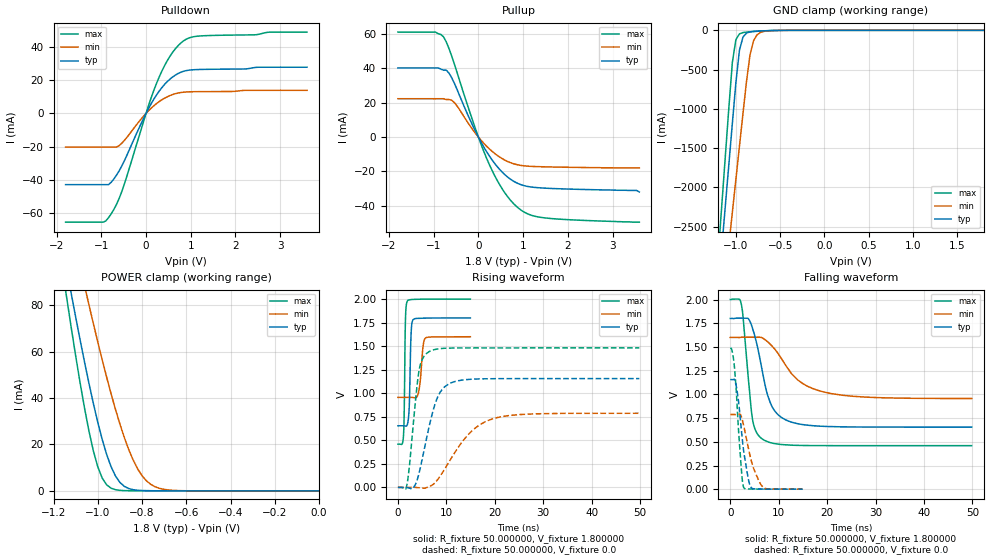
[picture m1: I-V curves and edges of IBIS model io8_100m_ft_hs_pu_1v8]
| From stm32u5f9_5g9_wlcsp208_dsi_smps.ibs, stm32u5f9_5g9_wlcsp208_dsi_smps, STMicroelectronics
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|   Model io8_100m_ft_hs_pu_1v8
[Model]  io8_100m_ft_hs_pu_1v8
Model_type I/O
Polarity   Non-Inverting
Enable   Active-Low
Vinl =   0.540000V
Vinh =   1.260000V
Vmeas =  0.900000V
Cref =   50.000000pF
Rref =   100.000000M
Vref =   0.0V
C_comp   3.148300pF   3.147400pF   3.196500pF
[Temperature Range]   25.000000   0.140000k   -40.000000
[Pullup Reference]   1.800000V   1.600000V   2.000000V
[Pulldown Reference]   0.0V   0.0V   0.0V
[POWER Clamp Reference]   1.800000V   1.600000V   2.000000V
[GND Clamp Reference]   0.0V   0.0V   0.0V
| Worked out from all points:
|   slope of the pulldown table from 0 to 0.27 V, typ, clamps not added: 21.7 ohm
|   slope of the pullup table from 0 to 0.27 V, typ, clamps not added: 22.6 ohm
|   GND clamp passes 1 mA (typ) near -0.51 V on its own axis
|   POWER clamp passes 1 mA (typ) near -0.86 V on its own axis
|   rising waveform, R_fixture 50.000000, V_fixture 1.800000: 20-80 % time 320ps typ, 625ps min, 232ps max; typ from 0.655 V to 1.8 V
|   rising waveform, R_fixture 50.000000, V_fixture 0.0: 20-80 % time 3.21ns typ, 6.76ns min, 1.69ns max; typ from 0.001 V to 1.16 V
|   falling waveform, R_fixture 50.000000, V_fixture 1.800000: 20-80 % time 3.22ns typ, 6.73ns min, 1.65ns max; typ from 1.8 V to 0.655 V
|   falling waveform, R_fixture 50.000000, V_fixture 0.0: 20-80 % time 1.6ns typ, 2.38ns min, 1.14ns max; typ from 1.16 V to 0.001 V
[Pulldown]
|Voltage   I(typ)   I(min)   I(max)
-1.8V     -42.74mA   -20.21mA   -65.25mA
-960mV    -42.74mA   -20.21mA   -65.25mA
-780mV    -41.3mA    -20.21mA   -60.25mA
-660mV    -37mA      -20.2mA    -54.5mA
-540mV    -31.39mA   -17.82mA   -46.65mA
0V        0A         0A         0A
240mV     11.28mA    6.002mA    18.38mA
480mV     19.17mA    10.02mA    31.83mA
780mV     24.67mA    12.5mA     42.21mA
960mV     25.9mA     12.9mA     45.21mA
1.2V      26.29mA    13.01mA    46.37mA
3.6V      27.65mA    13.81mA    48.71mA
[Pullup]
|Voltage   I(typ)   I(min)   I(max)
-1.8V     40.31mA    22.36mA    61.21mA
-960mV    40.31mA    22.36mA    61.21mA
-780mV    39.02mA    22.36mA    58.45mA
-660mV    37.4mA     21.91mA    51.75mA
-540mV    31.51mA    20.18mA    42.77mA
-120mV    6.338mA    4.065mA    8.965mA
240mV     -10.82mA   -6.752mA   -15.73mA
540mV     -20.62mA   -12.68mA   -30.5mA
900mV     -27.22mA   -16.28mA   -41.49mA
1.14V     -28.94mA   -17mA      -45.14mA
1.5V      -29.77mA   -17.34mA   -47.14mA
3.6V      -32mA      -18mA      -49.6mA
[GND_clamp]
|Voltage   I(typ)   I(min)   I(max)
-1.8V     -9.707A    -9.942A    -9.774A
-1.2V     -3.309A    -4.006A    -2.864A
-1.16V    -2.777A    -3.584A    -2.239A
-1.12V    -2.246A    -3.162A    -1.614A
-1.04V    -1.186A    -2.319A    -408.6mA
-1V       -663.9mA   -1.898A    -117.8mA
-960mV    -254mA     -1.478A    -45.14mA
-920mV    -86.03mA   -1.06A     -28.58mA
-840mV    -19.12mA   -308.9mA   -18.74mA
-800mV    -13.39mA   -130.8mA   -15.31mA
-720mV    -7.948mA   -25.37mA   -9.381mA
1.8V      0A         14.97nA    0A
[POWER_clamp]
|Voltage   I(typ)   I(min)   I(max)
-1.8V     470.9mA    433.7mA    554.6mA
-1.14V    95.28mA    122.7mA    82.88mA
-1.12V    85mA       114mA      70.34mA
-1.06V    55.55mA    88.43mA    35.73mA
-1.04V    46.38mA    80.17mA    25.83mA
-1V       29.54mA    64.14mA    10.37mA
-940mV    10.43mA    41.88mA    1.177mA
-900mV    3.66mA     28.79mA    250.5uA
-840mV    527.2uA    13.26mA    95.74uA
-800mV    153.8uA    6.55mA     88.56uA
-740mV    60.02uA    1.742mA    70.74uA
0V        0A         18.15nA    0A
[Ramp]
| variable   typ   min   max
dV/dt_r  0.69287/3.20241n   0.47199/6.75267n   0.88855/1.68963n
dV/dt_f  0.68715/3.21683n   0.38620/6.71772n   0.92440/1.65102n
R_load = 50.000000
[Rising Waveform]
R_fixture= 50.000000
V_fixture= 1.800000
V_fixture_min= 1.600000
V_fixture_max= 2.000000
|time   V(typ)   V(min)   V(max)
0s        654.8mV    956mV      459.4mV
1.141ns   654.6mV    956mV      544.2mV
1.562ns   651.7mV    956mV      1.793V
1.922ns   664.5mV    956.1mV    1.977V
2.312ns   832.9mV    956.1mV    1.991V
2.733ns   1.647V     955.9mV    1.995V
3.123ns   1.78V      954.9mV    1.996V
4.324ns   1.795V     1.027V     1.998V
5.676ns   1.798V     1.586V     1.999V
14.95ns   1.8V       1.6V       2V
[Rising Waveform]
R_fixture= 50.000000
V_fixture= 0.0
V_fixture_min= 0.0
V_fixture_max= 0.0
|time   V(typ)   V(min)   V(max)
0s        614.4uV    691.1uV    579uV
1.802ns   -969.1uV   688.6uV    15.4mV
3.003ns   -12.87mV   799.3uV    577.5mV
4.304ns   139.8mV    -3.18mV    1.223V
6.406ns   638mV      8.75mV     1.441V
8.008ns   935.3mV    71.01mV    1.469V
9.61ns    1.066V     191.7mV    1.478V
14.41ns   1.146V     554.9mV    1.481V
18.92ns   1.154V     716.9mV    1.481V
49.85ns   1.155V     787.4mV    1.481V
[Falling Waveform]
R_fixture= 50.000000
V_fixture= 1.800000
V_fixture_min= 1.600000
V_fixture_max= 2.000000
|time   V(typ)   V(min)   V(max)
0s        1.8V       1.6V       2V
2.302ns   1.804V     1.602V     1.946V
4.605ns   1.695V     1.603V     734mV
5.506ns   1.526V     1.602V     591.6mV
7.007ns   1.143V     1.582V     516.6mV
8.408ns   894.7mV    1.521V     489.5mV
10.11ns   774.9mV    1.412V     474mV
13.91ns   690.8mV    1.153V     462.5mV
18.42ns   665mV      1.037V     459.8mV
49.85ns   654.8mV    956mV      459.4mV
[Falling Waveform]
R_fixture= 50.000000
V_fixture= 0.0
V_fixture_min= 0.0
V_fixture_max= 0.0
|time   V(typ)   V(min)   V(max)
0s        1.155V     787.4mV    1.481V
270.3ps   1.155V     787.4mV    1.479V
660.7ps   1.156V     787.4mV    1.377V
1.231ns   1.091V     787.4mV    1.044V
1.682ns   935.7mV    788.4mV    643.8mV
2.252ns   646.4mV    770.7mV    236.8mV
2.763ns   406.1mV    672.2mV    19.93mV
4.144ns   31.46mV    340.5mV    2.096mV
6.787ns   1.826mV    20.06mV    1.003mV
14.95ns   614.4uV    691.1uV    579uV
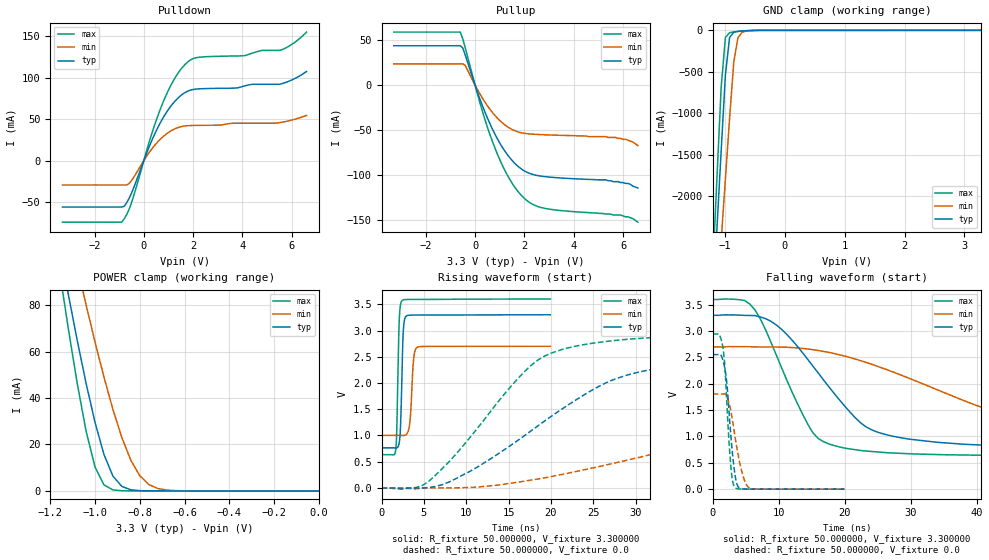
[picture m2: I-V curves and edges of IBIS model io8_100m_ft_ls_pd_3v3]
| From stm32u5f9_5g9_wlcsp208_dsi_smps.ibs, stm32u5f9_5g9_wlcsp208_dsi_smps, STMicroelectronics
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|   Model io8_100m_ft_ls_pd_3v3
[Model]  io8_100m_ft_ls_pd_3v3
Model_type I/O
Polarity   Non-Inverting
Enable   Active-Low
Vinl =   0.990000V
Vinh =   2.310000V
Vmeas =  1.650000V
Cref =   50.000000pF
Rref =   100.000000M
Vref =   0.0V
C_comp   3.313100pF   3.281800pF   3.354500pF
[Temperature Range]   25.000000   0.140000k   -40.000000
[Pullup Reference]   3.300000V   2.700000V   3.600000V
[Pulldown Reference]   0.0V   0.0V   0.0V
[POWER Clamp Reference]   3.300000V   2.700000V   3.600000V
[GND Clamp Reference]   0.0V   0.0V   0.0V
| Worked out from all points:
|   slope of the pulldown table from 0 to 0.495 V, typ, clamps not added: 14 ohm
|   slope of the pullup table from 0 to 0.495 V, typ, clamps not added: 13.7 ohm
|   GND clamp passes 1 mA (typ) near -0.50 V on its own axis
|   POWER clamp passes 1 mA (typ) near -0.85 V on its own axis
|   rising waveform, R_fixture 50.000000, V_fixture 3.300000: 20-80 % time 251ps typ, 341ps min, 235ps max; typ from 0.764 V to 3.3 V
|   rising waveform, R_fixture 50.000000, V_fixture 0.0: 20-80 % time 14.6ns typ, 31.2ns min, 9.33ns max; typ from 0 V to 2.55 V
|   falling waveform, R_fixture 50.000000, V_fixture 3.300000: 20-80 % time 10ns typ, 23.1ns min, 6.36ns max; typ from 3.3 V to 0.764 V
|   falling waveform, R_fixture 50.000000, V_fixture 0.0: 20-80 % time 1.02ns typ, 1.54ns min, 817ps max; typ from 2.55 V to 0 V
[Pulldown]
|Voltage   I(typ)   I(min)   I(max)
-3.3V     -56.06mA   -29.42mA   -74.35mA
-900mV    -56.06mA   -29.42mA   -74.35mA
-700mV    -51.09mA   -29.42mA   -65.48mA
-500mV    -39.32mA   -24.2mA    -50.88mA
300mV     22.62mA    13.13mA    30.42mA
800mV     52.54mA    29.36mA    71.75mA
1.3V      72.91mA    38.82mA    101.4mA
1.8V      84.02mA    42.13mA    119.4mA
2.2V      86.43mA    42.46mA    124.5mA
5.5V      91.98mA    45.75mA    132.9mA
6.1V      98.6mA     49.6mA     142.1mA
6.6V      107.5mA    54.5mA     155mA
[Pullup]
|Voltage   I(typ)   I(min)   I(max)
-3.3V     43.8mA     23.72mA    58.97mA
-600mV    43.8mA     23.72mA    58.97mA
-500mV    41.28mA    23.72mA    51.53mA
-400mV    33.57mA    21.9mA     41.51mA
300mV     -22.93mA   -14.5mA    -29.27mA
800mV     -54.04mA   -33.36mA   -69.41mA
1.4V      -80.24mA   -47.59mA   -104.2mA
2.1V      -96.56mA   -53.73mA   -127.9mA
3V        -101.9mA   -55.18mA   -137.5mA
5.7V      -107mA     -58mA      -144mA
6.2V      -109mA     -61mA      -146mA
6.6V      -114mA     -67mA      -152mA
[GND_clamp]
|Voltage   I(typ)   I(min)   I(max)
-3.3V     -9.848A    -9.957A    -9.458A
-1.2V     -3.312A    -4.013A    -2.863A
-1.13V    -2.381A    -3.274A    -1.769A
-1.06V    -1.452A    -2.535A    -684.8mA
-990mV    -542.9mA   -1.798A    -88.04mA
-920mV    -87.13mA   -1.064A    -28.45mA
-850mV    -22.11mA   -382.4mA   -19.62mA
-780mV    -11.98mA   -86.98mA   -13.73mA
-710mV    -7.63mA    -22.27mA   -8.759mA
-640mV    -4.504mA   -7.781mA   -4.831mA
-360mV    -39.8uA    -178.9uA   -19.56uA
3.28V     83.52uA    56.87uA    102.4uA
[POWER_clamp]
|Voltage   I(typ)   I(min)   I(max)
-3.28V    1.355A     1.167A     1.664A
-1.16V    105.7mA    131.6mA    95.69mA
-1.12V    84.97mA    114mA      70.27mA
-1.08V    65.05mA    96.83mA    46.54mA
-1.04V    46.34mA    80.15mA    25.76mA
-1V       29.51mA    64.13mA    10.3mA
-960mV    15.69mA    48.99mA    2.571mA
-920mV    6.373mA    35.1mA     455.6uA
-840mV    490.7uA    13.24mA    11.36uA
-760mV    27.33uA    2.767mA    276.6nA
-640mV    346.6nA    134.1uA    15.62nA
0V        0A         19.91nA    0A
[Ramp]
| variable   typ   min   max
dV/dt_r  1.53198/14.61283n   1.08390/31.21037n   1.76610/9.31984n
dV/dt_f  1.52119/10.01542n   1.01874/23.04554n   1.77923/6.35235n
R_load = 50.000000
[Rising Waveform]
R_fixture= 50.000000
V_fixture= 3.300000
V_fixture_min= 2.700000
V_fixture_max= 3.600000
|time   V(typ)   V(min)   V(max)
0s        763.9mV    1.001V     633.7mV
1.682ns   762.1mV    1.001V     731.3mV
2.082ns   852.8mV    1.001V     3.161V
2.242ns   1.169V     1.001V     3.494V
2.442ns   2.343V     1V         3.573V
2.763ns   3.233V     1.002V     3.589V
3.323ns   3.292V     1.217V     3.592V
3.804ns   3.294V     2.474V     3.592V
4.204ns   3.295V     2.678V     3.592V
19.94ns   3.299V     2.699V     3.599V
[Rising Waveform]
R_fixture= 50.000000
V_fixture= 0.0
V_fixture_min= 0.0
V_fixture_max= 0.0
|time   V(typ)   V(min)   V(max)
0s        16.97nV    116.6nV    53.79nV
5.606ns   7.053mV    -445.1uV   129.4mV
11.21ns   387mV      14.86mV    1.114V
16.02ns   896.6mV    107.2mV    2.068V
19.22ns   1.27V      190.8mV    2.509V
27.23ns   2.053V     462.6mV    2.804V
35.24ns   2.34V      768.8mV    2.889V
59.26ns   2.52V      1.515V     2.939V
95.3ns    2.551V     1.753V     2.943V
398.8ns   2.553V     1.806V     2.943V
[Falling Waveform]
R_fixture= 50.000000
V_fixture= 3.300000
V_fixture_min= 2.700000
V_fixture_max= 3.600000
|time   V(typ)   V(min)   V(max)
0s        3.299V     2.699V     3.599V
4.805ns   3.297V     2.704V     3.582V
6.406ns   3.293V     2.7V       3.4V
10.41ns   3.034V     2.697V     2.308V
16.02ns   2.199V     2.631V     958.7mV
22.42ns   1.256V     2.437V     733.4mV
26.43ns   1.029V     2.265V     691.3mV
47.25ns   808mV      1.344V     639.5mV
76.88ns   770.4mV    1.085V     634.1mV
398.8ns   763.9mV    1.001V     633.7mV
[Falling Waveform]
R_fixture= 50.000000
V_fixture= 0.0
V_fixture_min= 0.0
V_fixture_max= 0.0
|time   V(typ)   V(min)   V(max)
0s        2.553V     1.806V     2.943V
920.9ps   2.553V     1.806V     2.943V
1.562ns   2.437V     1.807V     2.658V
1.842ns   2.277V     1.81V      2.312V
2.082ns   2.07V      1.762V     1.751V
2.683ns   1.099V     1.52V      509.2mV
3.323ns   308.5mV    1.031V     36.82mV
4.484ns   4.69mV     293mV      1.824mV
5.606ns   952.3uV    16.21mV    1.484mV
19.94ns   16.97nV    116.6nV    53.79nV
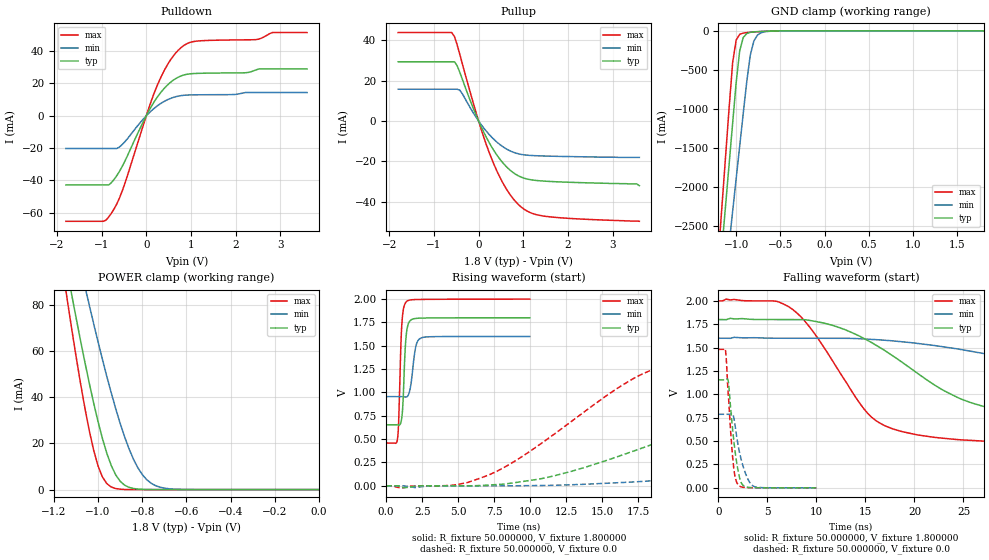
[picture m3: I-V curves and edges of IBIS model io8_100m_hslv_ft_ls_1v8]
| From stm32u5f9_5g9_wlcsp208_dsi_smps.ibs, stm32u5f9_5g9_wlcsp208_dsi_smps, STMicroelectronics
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|   Model io8_100m_hslv_ft_ls_1v8
[Model]  io8_100m_hslv_ft_ls_1v8
Model_type I/O
Polarity   Non-Inverting
Enable   Active-Low
Vinl =   0.540000V
Vinh =   1.260000V
Vmeas =  0.900000V
Cref =   50.000000pF
Rref =   100.000000M
Vref =   0.0V
C_comp   3.235100pF   3.233100pF   3.282800pF
[Temperature Range]   25.000000   0.140000k   -40.000000
[Pullup Reference]   1.800000V   1.600000V   2.000000V
[Pulldown Reference]   0.0V   0.0V   0.0V
[POWER Clamp Reference]   1.800000V   1.600000V   2.000000V
[GND Clamp Reference]   0.0V   0.0V   0.0V
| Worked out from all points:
|   slope of the pulldown table from 0 to 0.27 V, typ, clamps not added: 21.7 ohm
|   slope of the pullup table from 0 to 0.27 V, typ, clamps not added: 22.6 ohm
|   GND clamp passes 1 mA (typ) near -0.51 V on its own axis
|   POWER clamp passes 1 mA (typ) near -0.86 V on its own axis
|   rising waveform, R_fixture 50.000000, V_fixture 1.800000: 20-80 % time 203ps typ, 315ps min, 190ps max; typ from 0.654 V to 1.8 V
|   rising waveform, R_fixture 50.000000, V_fixture 0.0: 20-80 % time 14.5ns typ, 29.3ns min, 8.35ns max; typ from 0 V to 1.16 V
|   falling waveform, R_fixture 50.000000, V_fixture 1.800000: 20-80 % time 11.3ns typ, 24.9ns min, 6.01ns max; typ from 1.8 V to 0.654 V
|   falling waveform, R_fixture 50.000000, V_fixture 0.0: 20-80 % time 734ps typ, 1ns min, 580ps max; typ from 1.16 V to 0 V
[Pulldown]
|Voltage   I(typ)   I(min)   I(max)
-1.8V     -42.74mA   -20.21mA   -65.25mA
-960mV    -42.74mA   -20.21mA   -65.25mA
-780mV    -41.3mA    -20.21mA   -60.25mA
-540mV    -31.39mA   -17.82mA   -46.65mA
0V        -10fA      -1pA       10fA
240mV     11.28mA    6.001mA    18.38mA
480mV     19.18mA    10.01mA    31.83mA
780mV     24.67mA    12.49mA    42.21mA
1.14V     26.24mA    12.99mA    46.23mA
2.46V     28.42mA    14.38mA    47.14mA
2.82V     29mA       14.38mA    51.49mA
3.6V      29mA       14.38mA    51.49mA
[Pullup]
|Voltage   I(typ)   I(min)   I(max)
-1.8V     29.28mA    15.71mA    43.71mA
-600mV    29.28mA    15.71mA    43.71mA
-540mV    29.28mA    15.71mA    41.72mA
-420mV    24.04mA    15.23mA    32.87mA
0V        630fA      250pA      0A
300mV     -13.1mA    -8.157mA   -19.11mA
600mV     -22.1mA    -13.53mA   -32.82mA
780mV     -25.61mA   -15.48mA   -38.6mA
960mV     -27.82mA   -16.55mA   -42.66mA
1.2V      -29.16mA   -17.08mA   -45.68mA
1.56V     -29.85mA   -17.37mA   -47.3mA
3.6V      -32mA      -18mA      -49.6mA
[GND_clamp]
|Voltage   I(typ)   I(min)   I(max)
-1.8V     -9.707A    -9.942A    -9.774A
-1.2V     -3.309A    -4.006A    -2.864A
-1.16V    -2.777A    -3.584A    -2.239A
-1.12V    -2.246A    -3.162A    -1.614A
-1.04V    -1.186A    -2.319A    -408.6mA
-1V       -663.9mA   -1.898A    -117.8mA
-960mV    -254mA     -1.478A    -45.14mA
-920mV    -86.03mA   -1.06A     -28.58mA
-840mV    -19.12mA   -308.9mA   -18.74mA
-800mV    -13.39mA   -130.8mA   -15.31mA
-720mV    -7.948mA   -25.37mA   -9.381mA
1.8V      0A         14.95nA    0A
[POWER_clamp]
|Voltage   I(typ)   I(min)   I(max)
-1.8V     470.8mA    433.7mA    554.6mA
-1.14V    95.25mA    122.7mA    82.82mA
-1.12V    84.97mA    114mA      70.27mA
-1.06V    55.51mA    88.42mA    35.67mA
-1.04V    46.34mA    80.15mA    25.76mA
-1V       29.51mA    64.13mA    10.3mA
-940mV    10.39mA    41.86mA    1.109mA
-900mV    3.624mA    28.77mA    182.8uA
-840mV    490.7uA    13.24mA    11.35uA
-800mV    116.8uA    6.532mA    1.77uA
-740mV    13.2uA     1.723mA    109.2nA
0V        0A         18.72nA    0A
[Ramp]
| variable   typ   min   max
dV/dt_r  0.69300/14.45421n   0.47195/29.22630n   0.88872/8.33826n
dV/dt_f  0.68760/11.29167n   0.38671/24.86349n   0.92482/5.99901n
R_load = 50.000000
[Rising Waveform]
R_fixture= 50.000000
V_fixture= 1.800000
V_fixture_min= 1.600000
V_fixture_max= 2.000000
|time   V(typ)   V(min)   V(max)
0s        654mV      955.5mV    458.7mV
780.8ps   653.1mV    955.4mV    495.3mV
860.9ps   650.6mV    955.5mV    662.9mV
1.021ns   677.9mV    955.5mV    1.502V
1.101ns   749.8mV    955.3mV    1.759V
1.421ns   1.65V      952.5mV    1.975V
1.702ns   1.774V     1.069V     1.992V
2.062ns   1.793V     1.494V     1.996V
2.382ns   1.797V     1.58V      1.997V
9.97ns    1.8V       1.6V       2V
[Rising Waveform]
R_fixture= 50.000000
V_fixture= 0.0
V_fixture_min= 0.0
V_fixture_max= 0.0
|time   V(typ)   V(min)   V(max)
0s        2.188nV    146.3nV    1.494nV
6.006ns   571.9uV    -349.3uV   53.61mV
11.21ns   91.01mV    4.452mV    502.5mV
18.02ns   418.3mV    49.43mV    1.214V
21.62ns   612.1mV    99.83mV    1.36V
26.83ns   850.6mV    193.4mV    1.435V
32.03ns   1.002V     295.3mV    1.462V
39.64ns   1.095V     435.9mV    1.476V
68.87ns   1.152V     724.2mV    1.481V
199.4ns   1.155V     786.7mV    1.481V
[Falling Waveform]
R_fixture= 50.000000
V_fixture= 1.800000
V_fixture_min= 1.600000
V_fixture_max= 2.000000
|time   V(typ)   V(min)   V(max)
0s        1.8V       1.6V       2V
7.207ns   1.8V       1.6V       1.935V
9.209ns   1.793V     1.6V       1.732V
11.61ns   1.739V     1.6V       1.363V
16.02ns   1.529V     1.586V     722.7mV
18.82ns   1.337V     1.561V     599.4mV
24.42ns   965.2mV    1.486V     515.8mV
36.04ns   738.6mV    1.248V     471.5mV
63.66ns   663.4mV    1.021V     459mV
199.4ns   654mV      955.5mV    458.7mV
[Falling Waveform]
R_fixture= 50.000000
V_fixture= 0.0
V_fixture_min= 0.0
V_fixture_max= 0.0
|time   V(typ)   V(min)   V(max)
0s        1.155V     786.7mV    1.481V
720.7ps   1.155V     786.9mV    1.464V
800.8ps   1.157V     787mV      1.367V
1.001ns   1.137V     787.1mV    995.8mV
1.461ns   605.1mV    790.2mV    309.4mV
1.662ns   417mV      688.8mV    136mV
1.982ns   192.2mV    468.5mV    36.7mV
2.462ns   32.1mV     247.9mV    6.991mV
3.483ns   1.827mV    22.67mV    1.36mV
9.97ns    2.188nV    146.3nV    1.494nV
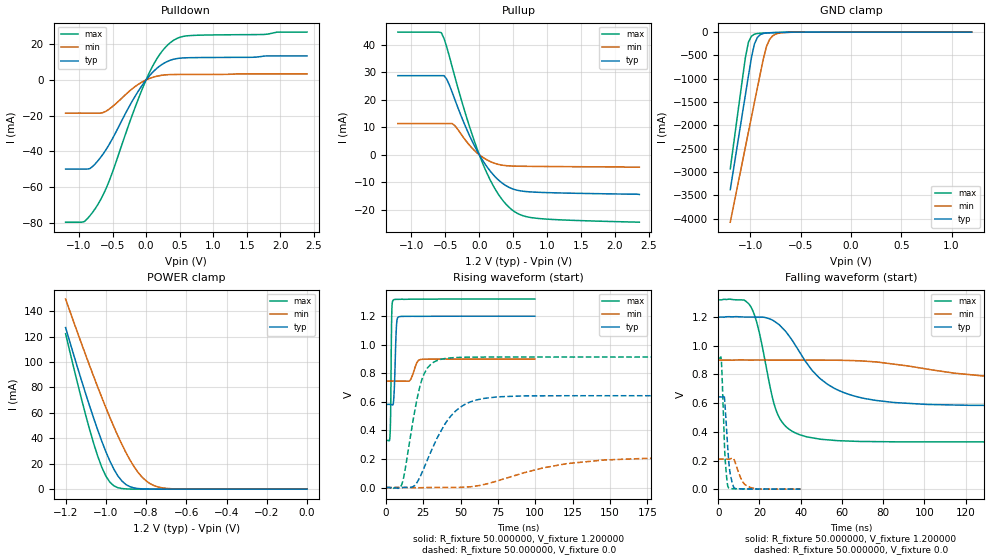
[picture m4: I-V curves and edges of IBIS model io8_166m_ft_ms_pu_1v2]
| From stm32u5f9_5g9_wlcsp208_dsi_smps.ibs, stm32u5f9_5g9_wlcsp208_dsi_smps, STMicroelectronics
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|   Model io8_166m_ft_ms_pu_1v2
[Model]  io8_166m_ft_ms_pu_1v2
Model_type I/O
Polarity   Non-Inverting
Enable   Active-Low
Vinl =   0.360000V
Vinh =   0.840000V
Vmeas =  0.600000V
Cref =   50.000000pF
Rref =   100.000000M
Vref =   0.0V
C_comp   3.151500pF   3.086800pF   3.197700pF
[Temperature Range]   25.000000   0.140000k   -40.000000
[Pullup Reference]   1.200000V   0.900000V   1.320000V
[Pulldown Reference]   0.0V   0.0V   0.0V
[POWER Clamp Reference]   1.200000V   0.900000V   1.320000V
[GND Clamp Reference]   0.0V   0.0V   0.0V
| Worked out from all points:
|   slope of the pulldown table from 0 to 0.18 V, typ, clamps not added: 25.4 ohm
|   slope of the pullup table from 0 to 0.18 V, typ, clamps not added: 27.8 ohm
|   GND clamp passes 1 mA (typ) near -0.51 V on its own axis
|   POWER clamp passes 1 mA (typ) near -0.86 V on its own axis
|   rising waveform, R_fixture 50.000000, V_fixture 1.200000: 20-80 % time 1.13ns typ, 3.03ns min, 564ps max; typ from 0.583 V to 1.2 V
|   rising waveform, R_fixture 50.000000, V_fixture 0.0: 20-80 % time 19.5ns typ, 48.4ns min, 9.61ns max; typ from 0 V to 0.643 V
|   falling waveform, R_fixture 50.000000, V_fixture 1.200000: 20-80 % time 22ns typ, 55.1ns min, 9.26ns max; typ from 1.2 V to 0.583 V
|   falling waveform, R_fixture 50.000000, V_fixture 0.0: 20-80 % time 1.97ns typ, 3.66ns min, 1.48ns max; typ from 0.643 V to 0 V
[Pulldown]
|Voltage   I(typ)   I(min)   I(max)
-1.2V     -49.86mA   -18.57mA   -79.56mA
-920mV    -49.86mA   -18.57mA   -79.19mA
-840mV    -49.6mA    -18.57mA   -76.08mA
-720mV    -45.32mA   -18.57mA   -69.74mA
-560mV    -36.71mA   -16.58mA   -57.44mA
-200mV    -11.43mA   -4.74mA    -19.03mA
0V        0A         0A         0A
160mV     6.477mA    2.075mA    11.78mA
360mV     10.99mA    2.99mA     20.81mA
480mV     12.07mA    3.054mA    23.52mA
640mV     12.43mA    3.075mA    24.76mA
2.4V      13.45mA    3.36mA     26.76mA
[Pullup]
|Voltage   I(typ)   I(min)   I(max)
-1.2V     28.72mA    11.35mA    44.55mA
-560mV    28.72mA    11.35mA    44.32mA
-480mV    27.44mA    11.35mA    39.12mA
-360mV    20.01mA    10.56mA    28.26mA
-160mV    7.809mA    3.931mA    11.44mA
40mV      -1.649mA   -721.3uA   -2.521mA
240mV     -8.14mA    -3.2mA     -12.72mA
360mV     -10.68mA   -3.85mA    -16.99mA
480mV     -12.27mA   -4.078mA   -19.94mA
640mV     -13.22mA   -4.169mA   -22.09mA
880mV     -13.63mA   -4.231mA   -23.13mA
2.36V     -14.4mA    -4.5mA     -24.47mA
[GND_clamp]
|Voltage   I(typ)   I(min)   I(max)
-1.2V     -3.379A    -4.076A    -2.932A
-1.05V    -1.35A     -2.47A     -550.7mA
-1.02V    -947.8mA   -2.149A    -221.5mA
-990mV    -552.4mA   -1.829A    -88.44mA
-960mV    -255.3mA   -1.51A     -44.87mA
-930mV    -111.8mA   -1.191A    -30.68mA
-870mV    -28.36mA   -564.6mA   -21.34mA
-840mV    -18.65mA   -309.5mA   -18.49mA
-810mV    -14.07mA   -161.6mA   -15.92mA
-780mV    -11.37mA   -83.33mA   -13.53mA
-600mV    -3.009mA   -4.322mA   -3.091mA
1.2V      0A         13.65nA    0A
[POWER_clamp]
|Voltage   I(typ)   I(min)   I(max)
-1.2V     127mA      149.4mA    122.2mA
-1.12V    84.98mA    114mA      70.29mA
-1.06V    55.52mA    88.42mA    35.69mA
-1.02V    37.64mA    72.04mA    17.19mA
-1V       29.52mA    64.13mA    10.33mA
-960mV    15.7mA     48.99mA    2.596mA
-900mV    3.636mA    28.77mA    207.8uA
-840mV    502.9uA    13.24mA    43.45uA
-800mV    129uA      6.535mA    43.45uA
-740mV    26.2uA     1.726mA    43.45uA
-620mV    25.1uA     82.33uA    35.72uA
0V        0A         17.36nA    0A
[Ramp]
| variable   typ   min   max
dV/dt_r  0.38568/19.48001n   0.12557/48.34419n   0.54818/9.59503n
dV/dt_f  0.37042/22.01517n   92.11800m/55.11116n 0.59405/9.23430n
R_load = 50.000000
[Rising Waveform]
R_fixture= 50.000000
V_fixture= 1.200000
V_fixture_min= 0.900000
V_fixture_max= 1.320000
|time   V(typ)   V(min)   V(max)
0s        582.6mV    746.1mV    329.9mV
2.803ns   582.7mV    746.1mV    368.2mV
3.203ns   582.7mV    746.1mV    514mV
3.604ns   582.2mV    746.1mV    961.6mV
4.004ns   580.8mV    746.1mV    1.244V
5.005ns   589.9mV    746.1mV    1.314V
7.007ns   1.115V     746.1mV    1.318V
8.408ns   1.194V     746.1mV    1.318V
23.22ns   1.199V     897.1mV    1.32V
99.7ns    1.2V       900mV      1.32V
[Rising Waveform]
R_fixture= 50.000000
V_fixture= 0.0
V_fixture_min= 0.0
V_fixture_max= 0.0
|time   V(typ)   V(min)   V(max)
0s        436.1uV    497.2uV    380.7uV
10.81ns   785.3uV    495.7uV    26.39mV
19.22ns   13.81mV    -487.7uV   529.6mV
23.42ns   87.3mV     -882.2uV   732.5mV
27.63ns   189.7mV    531.2uV    834.6mV
35.44ns   368.3mV    864.2uV    893.7mV
51.05ns   570.9mV    2.112mV    912.1mV
74.47ns   635mV      46.39mV    914.1mV
145.3ns   643.2mV    192.8mV    914.1mV
299.1ns   643.3mV    210mV      914mV
[Falling Waveform]
R_fixture= 50.000000
V_fixture= 1.200000
V_fixture_min= 0.900000
V_fixture_max= 1.320000
|time   V(typ)   V(min)   V(max)
0s        1.2V       900mV      1.32V
15.62ns   1.2V       900.6mV    1.277V
19.22ns   1.2V       900.8mV    1.134V
25.83ns   1.182V     900.5mV    668.5mV
28.83ns   1.155V     900.3mV    522.9mV
43.24ns   873.3mV    900mV      364.3mV
58.86ns   686mV      898.9mV    338mV
85.29ns   604.4mV    871.8mV    330.6mV
153.2ns   582.9mV    768mV      329.9mV
299.1ns   582.6mV    746.1mV    329.9mV
[Falling Waveform]
R_fixture= 50.000000
V_fixture= 0.0
V_fixture_min= 0.0
V_fixture_max= 0.0
|time   V(typ)   V(min)   V(max)
0s        643.3mV    210mV      914mV
1.522ns   643.2mV    210mV      896mV
2.803ns   656.2mV    210mV      407.9mV
3.283ns   591.3mV    210mV      232.1mV
4.885ns   237.6mV    209.6mV    12.88mV
5.926ns   101.4mV    212.1mV    5.245mV
8.168ns   5.342mV    189.9mV    2.977mV
11.85ns   1.875mV    52.05mV    2.74mV
15.22ns   1.518mV    15.19mV    2.304mV
39.88ns   436.1uV    497.2uV    380.7uV
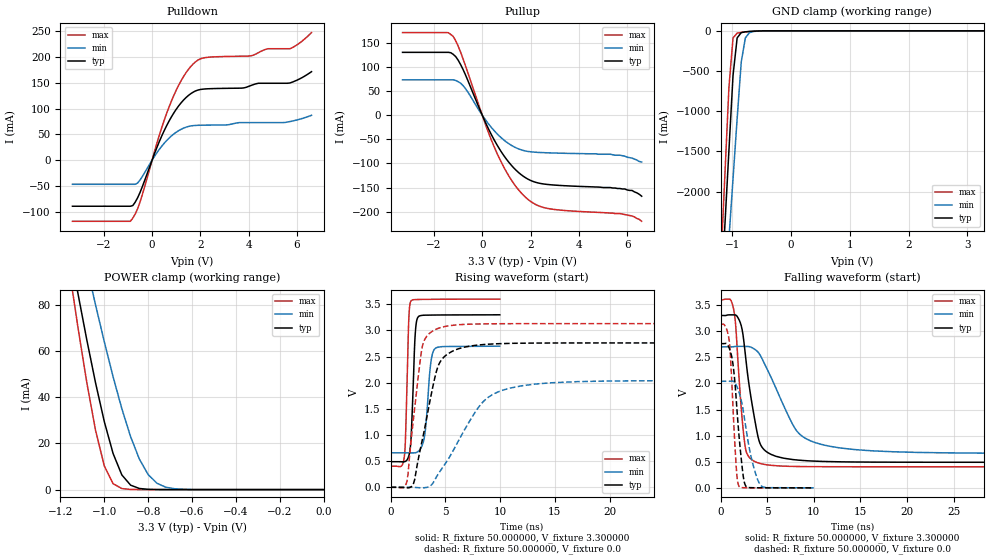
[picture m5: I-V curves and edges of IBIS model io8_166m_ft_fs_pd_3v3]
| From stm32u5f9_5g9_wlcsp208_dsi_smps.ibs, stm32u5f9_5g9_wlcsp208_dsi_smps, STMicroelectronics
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|   Model io8_166m_ft_fs_pd_3v3
[Model]  io8_166m_ft_fs_pd_3v3
Model_type I/O
Polarity   Non-Inverting
Enable   Active-Low
Vinl =   0.990000V
Vinh =   2.310000V
Vmeas =  1.650000V
Cref =   50.000000pF
Rref =   100.000000M
Vref =   0.0V
C_comp   3.517200pF   3.489400pF   3.557800pF
[Temperature Range]   25.000000   0.140000k   -40.000000
[Pullup Reference]   3.300000V   2.700000V   3.600000V
[Pulldown Reference]   0.0V   0.0V   0.0V
[POWER Clamp Reference]   3.300000V   2.700000V   3.600000V
[GND Clamp Reference]   0.0V   0.0V   0.0V
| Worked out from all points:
|   slope of the pulldown table from 0 to 0.495 V, typ, clamps not added: 8.73 ohm
|   slope of the pullup table from 0 to 0.495 V, typ, clamps not added: 9.64 ohm
|   GND clamp passes 1 mA (typ) near -0.50 V on its own axis
|   POWER clamp passes 1 mA (typ) near -0.85 V on its own axis
|   rising waveform, R_fixture 50.000000, V_fixture 3.300000: 20-80 % time 303ps typ, 461ps min, 244ps max; typ from 0.49 V to 3.3 V
|   rising waveform, R_fixture 50.000000, V_fixture 0.0: 20-80 % time 1.63ns typ, 3.59ns min, 1.01ns max; typ from 0 V to 2.76 V
|   falling waveform, R_fixture 50.000000, V_fixture 3.300000: 20-80 % time 1.39ns typ, 3.34ns min, 786ps max; typ from 3.3 V to 0.49 V
|   falling waveform, R_fixture 50.000000, V_fixture 0.0: 20-80 % time 787ps typ, 1.27ns min, 541ps max; typ from 2.76 V to 0 V
[Pulldown]
|Voltage   I(typ)   I(min)   I(max)
-3.3V     -89.72mA   -47.06mA   -119mA
-900mV    -89.72mA   -47.06mA   -119mA
-500mV    -62.92mA   -38.71mA   -81.44mA
300mV     36.2mA     21.01mA    48.7mA
800mV     84.07mA    46.96mA    114.9mA
1.3V      116.7mA    62.09mA    162.4mA
1.8V      134.4mA    67.39mA    191.2mA
2.3V      138.6mA    67.98mA    199.8mA
4.1V      145.1mA    72.79mA    202.7mA
4.8V      149.4mA    72.79mA    216.5mA
5.7V      149.8mA    74.8mA     216.5mA
6.6V      171.9mA    87.1mA     247.9mA
[Pullup]
|Voltage   I(typ)   I(min)   I(max)
-3.3V     130.3mA    73.27mA    171.3mA
-1.4V     130.3mA    73.27mA    171mA
-1.2V     126mA      73.27mA    163.1mA
-1V       114.2mA    69.44mA    143.5mA
-800mV    95.36mA    61.6mA     117.5mA
100mV     -11.39mA   -7.258mA   -14.51mA
600mV     -60.65mA   -37.83mA   -77.68mA
1.2V      -103.6mA   -62.35mA   -134mA
1.9V      -132.8mA   -75.24mA   -174.9mA
2.7V      -143.6mA   -78mA      -193.2mA
5.9V      -153mA     -85mA      -206mA
6.6V      -168mA     -97mA      -220mA
[GND_clamp]
|Voltage   I(typ)   I(min)   I(max)
-3.3V     -9.098A    -9.372A    -9.671A
-1.2V     -3.386A    -4.091A    -2.933A
-1.13V    -2.437A    -3.34A     -1.815A
-1.06V    -1.49A     -2.588A    -705.6mA
-990mV    -555.7mA   -1.839A    -89.05mA
-920mV    -88.14mA   -1.093A    -28.79mA
-850mV    -22.37mA   -387.4mA   -19.86mA
-780mV    -12.13mA   -88.01mA   -13.89mA
-710mV    -7.72mA    -22.53mA   -8.86mA
-640mV    -4.556mA   -7.872mA   -4.884mA
-360mV    -39.7uA    -179.9uA   -19.45uA
3.28V     83.52uA    56.87uA    102.4uA
[POWER_clamp]
|Voltage   I(typ)   I(min)   I(max)
-3.28V    1.355A     1.167A     1.664A
-1.16V    105.7mA    131.6mA    95.69mA
-1.12V    84.97mA    114mA      70.27mA
-1.08V    65.05mA    96.83mA    46.54mA
-1.04V    46.34mA    80.15mA    25.76mA
-1V       29.51mA    64.13mA    10.3mA
-960mV    15.69mA    48.99mA    2.571mA
-920mV    6.373mA    35.1mA     455.6uA
-840mV    490.7uA    13.24mA    11.36uA
-760mV    27.33uA    2.767mA    278.3nA
-640mV    347.6nA    134.1uA    16.77nA
0V        0A         19.95nA    0A
[Ramp]
| variable   typ   min   max
dV/dt_r  1.65672/1.63177n   1.22418/3.58104n   1.87812/1.00608n
dV/dt_f  1.68577/1.38738n   1.22388/3.33295n   1.91752/0.78132n
R_load = 50.000000
[Rising Waveform]
R_fixture= 50.000000
V_fixture= 3.300000
V_fixture_min= 2.700000
V_fixture_max= 3.600000
|time   V(typ)   V(min)   V(max)
0s        489.8mV    659.5mV    403.4mV
1.261ns   488.5mV    659.5mV    595.7mV
1.662ns   601.1mV    659.4mV    3.198V
1.862ns   910.3mV    658.8mV    3.564V
2.222ns   2.828V     659.6mV    3.59V
2.503ns   3.254V     683.5mV    3.592V
3.123ns   3.292V     1.005V     3.595V
3.624ns   3.294V     2.293V     3.596V
3.984ns   3.295V     2.635V     3.596V
9.97ns    3.299V     2.699V     3.599V
[Rising Waveform]
R_fixture= 50.000000
V_fixture= 0.0
V_fixture_min= 0.0
V_fixture_max= 0.0
|time   V(typ)   V(min)   V(max)
0s        5.305uV    5.718uV    3.641uV
1.401ns   -9.165mV   40.95uV    53.24mV
1.602ns   -10.69mV   80.53uV    264.9mV
2.102ns   76.88mV    -992.9uV   1.33V
2.903ns   912.1mV    -9.303mV   2.699V
4.004ns   2.062V     127.7mV    3.008V
4.505ns   2.391V     303.4mV    3.051V
8.408ns   2.729V     1.626V     3.126V
12.01ns   2.756V     1.942V     3.13V
49.85ns   2.761V     2.04V      3.13V
[Falling Waveform]
R_fixture= 50.000000
V_fixture= 3.300000
V_fixture_min= 2.700000
V_fixture_max= 3.600000
|time   V(typ)   V(min)   V(max)
0s        3.299V     2.699V     3.599V
1.401ns   3.311V     2.703V     3.41V
1.602ns   3.309V     2.708V     3.127V
2.202ns   3.105V     2.709V     1.532V
2.703ns   2.46V      2.708V     717.6mV
3.904ns   1.064V     2.616V     485mV
4.905ns   693mV      2.301V     442.4mV
8.108ns   535.1mV    1.103V     409.5mV
11.11ns   505.1mV    818.5mV    404.9mV
49.85ns   489.8mV    659.5mV    403.4mV
[Falling Waveform]
R_fixture= 50.000000
V_fixture= 0.0
V_fixture_min= 0.0
V_fixture_max= 0.0
|time   V(typ)   V(min)   V(max)
0s        2.761V     2.04V      3.13V
500.5ps   2.764V     2.04V      3.091V
920.9ps   2.672V     2.04V      2.808V
1.301ns   2.387V     2.043V     1.61V
1.682ns   1.654V     1.96V      363.8mV
1.962ns   1.005V     1.835V     31.48mV
2.623ns   59.2mV     1.244V     2.384mV
3.343ns   3.129mV    532.5mV    1.33mV
4.284ns   1.389mV    51.75mV    867uV
9.97ns    5.305uV    5.718uV    3.641uV
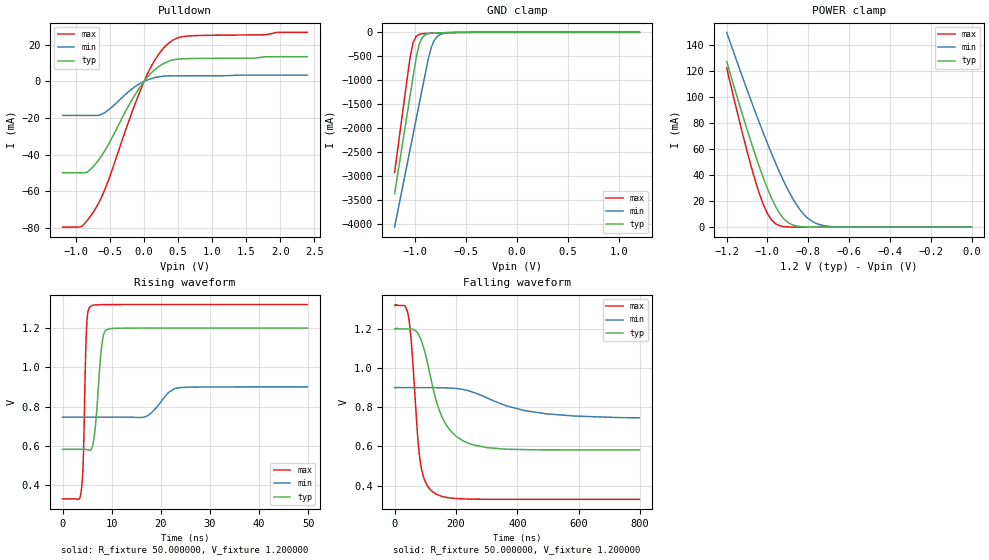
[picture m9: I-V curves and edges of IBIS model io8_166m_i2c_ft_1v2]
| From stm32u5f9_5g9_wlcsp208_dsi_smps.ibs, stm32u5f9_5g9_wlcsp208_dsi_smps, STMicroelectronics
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|   Model io8_166m_i2c_ft_1v2
[Model]  io8_166m_i2c_ft_1v2
Model_type I/O_open_drain
Polarity   Non-Inverting
Enable   Active-Low
Vinl =   0.360000V
Vinh =   0.840000V
Vmeas =  0.600000V
Cref =   50.000000pF
Rref =   100.000000M
Vref =   0.600000V
C_comp   3.158100pF   3.093400pF   3.204300pF
[Temperature Range]   25.000000   0.140000k   -40.000000
[Pullup Reference]   1.200000V   0.900000V   1.320000V
[Pulldown Reference]   0.0V   0.0V   0.0V
[POWER Clamp Reference]   1.200000V   0.900000V   1.320000V
[GND Clamp Reference]   0.0V   0.0V   0.0V
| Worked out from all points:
|   slope of the pulldown table from 0 to 0.18 V, typ, clamps not added: 25.4 ohm
|   GND clamp passes 1 mA (typ) near -0.51 V on its own axis
|   POWER clamp passes 1 mA (typ) near -0.86 V on its own axis
|   rising waveform, R_fixture 50.000000, V_fixture 1.200000: 20-80 % time 1.13ns typ, 3.03ns min, 555ps max; typ from 0.582 V to 1.2 V
|   falling waveform, R_fixture 50.000000, V_fixture 1.200000: 20-80 % time 70.8ns typ, 181ns min, 28.1ns max; typ from 1.2 V to 0.582 V
[Pulldown]
|Voltage   I(typ)   I(min)   I(max)
-1.2V     -49.86mA   -18.57mA   -79.57mA
-920mV    -49.86mA   -18.57mA   -79.2mA
-840mV    -49.6mA    -18.57mA   -76.08mA
-720mV    -45.32mA   -18.57mA   -69.74mA
-560mV    -36.71mA   -16.58mA   -57.44mA
-200mV    -11.43mA   -4.74mA    -19.03mA
0V        0A         -500fA     0A
160mV     6.477mA    2.075mA    11.78mA
360mV     10.99mA    2.989mA    20.81mA
480mV     12.07mA    3.054mA    23.53mA
640mV     12.43mA    3.074mA    24.76mA
2.4V      13.46mA    3.369mA    26.78mA
[GND_clamp]
|Voltage   I(typ)   I(min)   I(max)
-1.2V     -3.379A    -4.076A    -2.932A
-1.05V    -1.35A     -2.47A     -550.7mA
-1.02V    -947.8mA   -2.149A    -221.5mA
-990mV    -552.4mA   -1.829A    -88.44mA
-960mV    -255.3mA   -1.51A     -44.87mA
-930mV    -111.8mA   -1.191A    -30.68mA
-870mV    -28.36mA   -564.6mA   -21.34mA
-840mV    -18.65mA   -309.5mA   -18.49mA
-810mV    -14.07mA   -161.6mA   -15.92mA
-780mV    -11.37mA   -83.33mA   -13.53mA
-600mV    -3.009mA   -4.322mA   -3.091mA
1.2V      0A         13.65nA    0A
[POWER_clamp]
|Voltage   I(typ)   I(min)   I(max)
-1.2V     127mA      149.4mA    122.2mA
-1.12V    84.97mA    114mA      70.27mA
-1.06V    55.51mA    88.42mA    35.67mA
-1.02V    37.63mA    72.04mA    17.17mA
-1V       29.51mA    64.13mA    10.3mA
-960mV    15.69mA    48.99mA    2.571mA
-900mV    3.624mA    28.77mA    182.8uA
-840mV    490.7uA    13.24mA    11.35uA
-800mV    116.8uA    6.532mA    1.77uA
-740mV    13.2uA     1.724mA    109.1nA
-620mV    167.4nA    79.36uA    0A
0V        0A         17.87nA    0A
[Ramp]
| variable   typ   min   max
dV/dt_r  0.37074/1.12444n   92.38200m/3.02507n  0.59420/0.54886n
dV/dt_f  0.37085/70.72830n   91.08000m/0.18228u  0.59438/28.05877n
R_load = 50.000000
[Rising Waveform]
R_fixture= 50.000000
V_fixture= 1.200000
V_fixture_min= 0.900000
V_fixture_max= 1.320000
|time   V(typ)   V(min)   V(max)
0s        581.9mV    745.9mV    329.4mV
3.804ns   582mV      745.9mV    367.8mV
4.204ns   582mV      745.9mV    511.7mV
4.905ns   580.4mV    745.9mV    1.204V
5.706ns   578mV      745.9mV    1.31V
6.607ns   679.8mV    745.9mV    1.318V
8.008ns   1.114V     745.9mV    1.319V
8.909ns   1.191V     745.9mV    1.319V
24.02ns   1.2V       896.8mV    1.32V
49.85ns   1.2V       900mV      1.32V
[Falling Waveform]
R_fixture= 50.000000
V_fixture= 1.200000
V_fixture_min= 0.900000
V_fixture_max= 1.320000
|time   V(typ)   V(min)   V(max)
0s        1.2V       900mV      1.32V
43.24ns   1.2V       900mV      1.279V
54.45ns   1.2V       900mV      1.132V
75.28ns   1.179V     900mV      649.3mV
83.28ns   1.154V     900mV      524.8mV
124.9ns   899mV      900mV      366.9mV
174.6ns   695.6mV    898.4mV    337.8mV
259.5ns   606.3mV    874.3mV    330.2mV
424.4ns   583.4mV    782.5mV    329.3mV
797.6ns   581.9mV    745.9mV    329.4mV
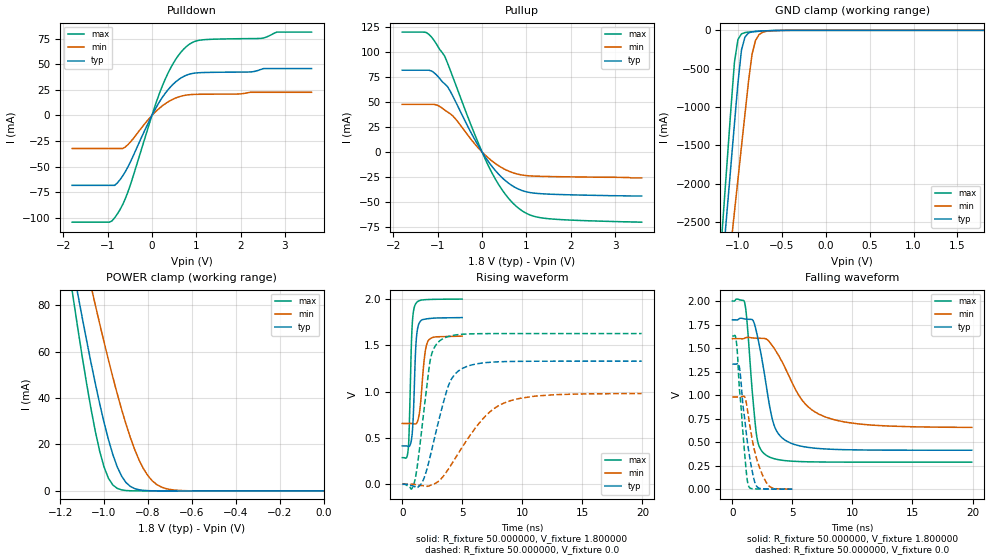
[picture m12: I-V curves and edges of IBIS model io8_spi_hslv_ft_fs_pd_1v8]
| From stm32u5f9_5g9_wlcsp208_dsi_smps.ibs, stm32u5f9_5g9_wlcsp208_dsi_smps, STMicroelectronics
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|   Model io8_spi_hslv_ft_fs_pd_1v8
[Model]  io8_spi_hslv_ft_fs_pd_1v8
Model_type I/O
Polarity   Non-Inverting
Enable   Active-Low
Vinl =   0.540000V
Vinh =   1.260000V
Vmeas =  0.900000V
Cref =   50.000000pF
Rref =   100.000000M
Vref =   0.0V
C_comp   3.338700pF   3.332500pF   3.379000pF
[Temperature Range]   25.000000   0.140000k   -40.000000
[Pullup Reference]   1.800000V   1.600000V   2.000000V
[Pulldown Reference]   0.0V   0.0V   0.0V
[POWER Clamp Reference]   1.800000V   1.600000V   2.000000V
[GND Clamp Reference]   0.0V   0.0V   0.0V
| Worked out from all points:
|   slope of the pulldown table from 0 to 0.27 V, typ, clamps not added: 13.6 ohm
|   slope of the pullup table from 0 to 0.27 V, typ, clamps not added: 15.9 ohm
|   GND clamp passes 1 mA (typ) near -0.50 V on its own axis
|   POWER clamp passes 1 mA (typ) near -0.86 V on its own axis
|   rising waveform, R_fixture 50.000000, V_fixture 1.800000: 20-80 % time 245ps typ, 388ps min, 218ps max; typ from 0.414 V to 1.8 V
|   rising waveform, R_fixture 50.000000, V_fixture 0.0: 20-80 % time 1.58ns typ, 3.31ns min, 900ps max; typ from 0 V to 1.33 V
|   falling waveform, R_fixture 50.000000, V_fixture 1.800000: 20-80 % time 1.19ns typ, 2.71ns min, 660ps max; typ from 1.8 V to 0.414 V
|   falling waveform, R_fixture 50.000000, V_fixture 0.0: 20-80 % time 773ps typ, 1.04ns min, 577ps max; typ from 1.33 V to 0 V
[Pulldown]
|Voltage   I(typ)   I(min)   I(max)
-1.8V     -68.38mA   -32.32mA   -104.4mA
-960mV    -68.38mA   -32.32mA   -104.4mA
-780mV    -66.07mA   -32.32mA   -96.42mA
-540mV    -50.22mA   -28.51mA   -74.66mA
0V        -10fA      -300fA     0A
240mV     18.04mA    9.599mA    29.41mA
480mV     30.68mA    16.02mA    50.95mA
780mV     39.47mA    19.98mA    67.56mA
1.14V     41.99mA    20.78mA    74.01mA
2.46V     45.09mA    22.69mA    75.44mA
2.82V     45.91mA    22.69mA    81.6mA
3.6V      45.91mA    22.69mA    81.6mA
[Pullup]
|Voltage   I(typ)   I(min)   I(max)
-1.8V     82.1mA     47.76mA    120.3mA
-1.26V    82.1mA     47.76mA    120mA
-1.08V    79.51mA    47.76mA    111.8mA
-840mV    68.28mA    42.01mA    95.94mA
-660mV    56.17mA    36.23mA    75.42mA
-240mV    18.69mA    12.2mA     26.01mA
120mV     -8.174mA   -5.123mA   -11.83mA
480mV     -26.98mA   -16.65mA   -39.76mA
840mV     -37.65mA   -22.63mA   -57.07mA
1.08V     -40.74mA   -24.01mA   -63.22mA
1.44V     -42.19mA   -24.58mA   -66.73mA
3.6V      -44.2mA    -26mA      -70.5mA
[GND_clamp]
|Voltage   I(typ)   I(min)   I(max)
-1.8V     -9.908A    -9.683A    -9.994A
-1.2V     -3.383A    -4.084A    -2.934A
-1.16V    -2.841A    -3.655A    -2.294A
-1.12V    -2.299A    -3.226A    -1.656A
-1.04V    -1.218A    -2.369A    -414.2mA
-1V       -684.7mA   -1.941A    -119.2mA
-960mV    -257.2mA   -1.514A    -45.67mA
-920mV    -87.04mA   -1.089A    -28.94mA
-840mV    -19.36mA   -312.8mA   -18.98mA
-800mV    -13.56mA   -132.4mA   -15.51mA
-720mV    -8.053mA   -25.67mA   -9.504mA
1.8V      45.71uA    33.32uA    56.11uA
[POWER_clamp]
|Voltage   I(typ)   I(min)   I(max)
-1.8V     470.8mA    433.7mA    554.6mA
-1.14V    95.25mA    122.7mA    82.82mA
-1.12V    84.97mA    114mA      70.27mA
-1.06V    55.51mA    88.42mA    35.67mA
-1.04V    46.34mA    80.15mA    25.76mA
-1V       29.51mA    64.13mA    10.3mA
-940mV    10.39mA    41.86mA    1.109mA
-900mV    3.624mA    28.77mA    182.8uA
-840mV    490.7uA    13.24mA    11.35uA
-800mV    116.8uA    6.532mA    1.77uA
-740mV    13.2uA     1.724mA    109.3nA
0V        0A         18.75nA    0A
[Ramp]
| variable   typ   min   max
dV/dt_r  0.79740/1.58327n   0.58747/3.31024n   0.97632/0.89788n
dV/dt_f  0.83141/1.18968n   0.56475/2.70533n   1.02743/0.65880n
R_load = 50.000000
[Rising Waveform]
R_fixture= 50.000000
V_fixture= 1.800000
V_fixture_min= 1.600000
V_fixture_max= 2.000000
|time   V(typ)   V(min)   V(max)
0s        413.8mV    656.5mV    287.2mV
500.5ps   409.7mV    656.6mV    382.3mV
570.6ps   409.5mV    656.6mV    561mV
800.8ps   513.7mV    656.3mV    1.648V
1.041ns   1.203V     651.3mV    1.927V
1.161ns   1.549V     655.3mV    1.957V
1.311ns   1.702V     694.9mV    1.975V
1.882ns   1.782V     1.403V     1.993V
2.142ns   1.788V     1.545V     1.995V
4.985ns   1.8V       1.599V     2V
[Rising Waveform]
R_fixture= 50.000000
V_fixture= 0.0
V_fixture_min= 0.0
V_fixture_max= 0.0
|time   V(typ)   V(min)   V(max)
0s        -10.72uV   84.57nV    3.206uV
1.001ns   -22.79mV   -585.4uV   16.58mV
1.642ns   17.71mV    -14.22mV   611.5mV
2.322ns   299mV      -13.12mV   1.334V
3.283ns   812.2mV    65.66mV    1.564V
3.964ns   1.102V     187.9mV    1.6V
4.645ns   1.22V      328.7mV    1.615V
6.607ns   1.308V     690.6mV    1.626V
8.328ns   1.324V     868.5mV    1.627V
19.94ns   1.329V     979.8mV    1.627V
[Falling Waveform]
R_fixture= 50.000000
V_fixture= 1.800000
V_fixture_min= 1.600000
V_fixture_max= 2.000000
|time   V(typ)   V(min)   V(max)
0s        1.8V       1.599V     2V
1.041ns   1.809V     1.606V     1.973V
1.682ns   1.799V     1.607V     1.002V
2.002ns   1.674V     1.605V     585.2mV
2.803ns   1.117V     1.598V     361.6mV
3.363ns   726.7mV    1.518V     328.2mV
4.004ns   562.4mV    1.385V     309.9mV
5.806ns   454.8mV    946.6mV    292.6mV
7.728ns   427.4mV    767.8mV    288.4mV
19.94ns   413.8mV    656.5mV    287.2mV
[Falling Waveform]
R_fixture= 50.000000
V_fixture= 0.0
V_fixture_min= 0.0
V_fixture_max= 0.0
|time   V(typ)   V(min)   V(max)
0s        1.329V     979.8mV    1.627V
320.3ps   1.329V     979.9mV    1.58V
430.4ps   1.335V     979.9mV    1.423V
580.6ps   1.3V       979.8mV    1.08V
1.051ns   718.1mV    973.4mV    337.7mV
1.221ns   531.1mV    871.7mV    114.9mV
1.351ns   412.5mV    761.1mV    33.47mV
1.922ns   54.94mV    370.3mV    2.817mV
2.823ns   2.721mV    71.53mV    987.4uV
4.985ns   -10.72uV   84.57nV    3.206uV
